VERSION 5.8 ;
BUSBITCHARS "[]" ;
DIVIDERCHAR "/" ;
UNITS
    DATABASE MICRONS 1000 ;
END UNITS

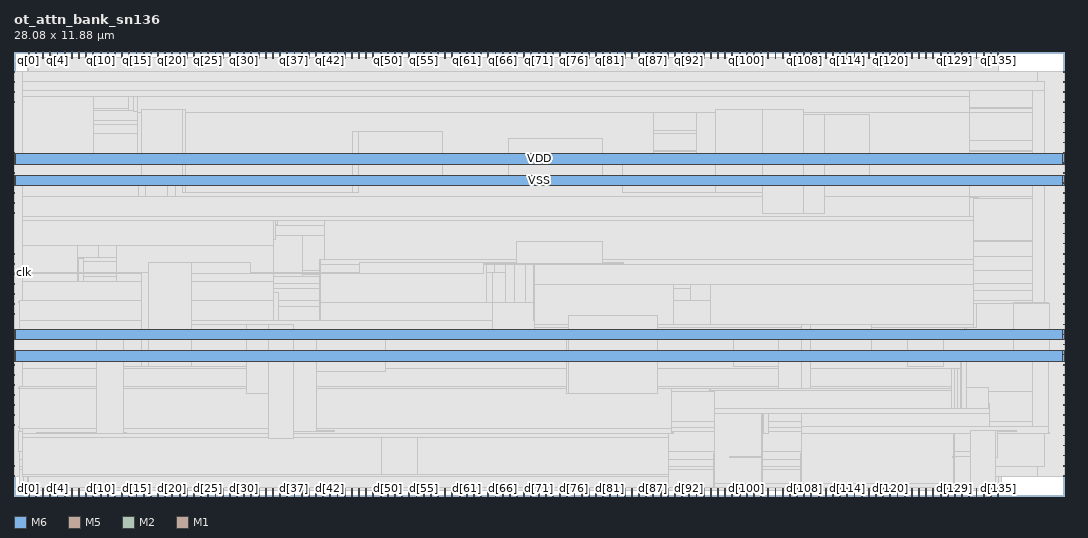
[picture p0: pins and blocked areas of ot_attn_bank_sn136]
MACRO ot_attn_bank_sn136
  FOREIGN ot_attn_bank_sn136 0 0 ;
  CLASS BLOCK ;
  SIZE 28.08 BY 11.88 ;
  PIN clk
    DIRECTION INPUT ;
    USE SIGNAL ;
    PORT
      LAYER M6 ;
        RECT  0 5.952 0.192 5.984 ;
    END
  END clk
  PIN d[0]
    DIRECTION INPUT ;
    USE SIGNAL ;
    PORT
      LAYER M5 ;
        RECT  0.384 0 0.408 0.192 ;
    END
  END d[0]
  PIN d[100]
    DIRECTION INPUT ;
    USE SIGNAL ;
    PORT
      LAYER M5 ;
        RECT  19.584 0 19.608 0.192 ;
    END
  END d[100]
  PIN d[101]
    DIRECTION INPUT ;
    USE SIGNAL ;
    PORT
      LAYER M5 ;
        RECT  19.776 0 19.8 0.192 ;
    END
  END d[101]
  PIN d[102]
    DIRECTION INPUT ;
    USE SIGNAL ;
    PORT
      LAYER M5 ;
        RECT  19.968 0 19.992 0.192 ;
    END
  END d[102]
  PIN d[103]
    DIRECTION INPUT ;
    USE SIGNAL ;
    PORT
      LAYER M5 ;
        RECT  20.16 0 20.184 0.192 ;
    END
  END d[103]
  PIN d[104]
    DIRECTION INPUT ;
    USE SIGNAL ;
    PORT
      LAYER M5 ;
        RECT  20.352 0 20.376 0.192 ;
    END
  END d[104]
  PIN d[105]
    DIRECTION INPUT ;
    USE SIGNAL ;
    PORT
      LAYER M5 ;
        RECT  20.544 0 20.568 0.192 ;
    END
  END d[105]
  PIN d[106]
    DIRECTION INPUT ;
    USE SIGNAL ;
    PORT
      LAYER M5 ;
        RECT  20.736 0 20.76 0.192 ;
    END
  END d[106]
  PIN d[107]
    DIRECTION INPUT ;
    USE SIGNAL ;
    PORT
      LAYER M5 ;
        RECT  20.928 0 20.952 0.192 ;
    END
  END d[107]
  PIN d[108]
    DIRECTION INPUT ;
    USE SIGNAL ;
    PORT
      LAYER M5 ;
        RECT  21.12 0 21.144 0.192 ;
    END
  END d[108]
  PIN d[109]
    DIRECTION INPUT ;
    USE SIGNAL ;
    PORT
      LAYER M5 ;
        RECT  21.312 0 21.336 0.192 ;
    END
  END d[109]
  PIN d[10]
    DIRECTION INPUT ;
    USE SIGNAL ;
    PORT
      LAYER M5 ;
        RECT  2.304 0 2.328 0.192 ;
    END
  END d[10]
  PIN d[110]
    DIRECTION INPUT ;
    USE SIGNAL ;
    PORT
      LAYER M5 ;
        RECT  21.504 0 21.528 0.192 ;
    END
  END d[110]
  PIN d[111]
    DIRECTION INPUT ;
    USE SIGNAL ;
    PORT
      LAYER M5 ;
        RECT  21.696 0 21.72 0.192 ;
    END
  END d[111]
  PIN d[112]
    DIRECTION INPUT ;
    USE SIGNAL ;
    PORT
      LAYER M5 ;
        RECT  21.888 0 21.912 0.192 ;
    END
  END d[112]
  PIN d[113]
    DIRECTION INPUT ;
    USE SIGNAL ;
    PORT
      LAYER M5 ;
        RECT  22.08 0 22.104 0.192 ;
    END
  END d[113]
  PIN d[114]
    DIRECTION INPUT ;
    USE SIGNAL ;
    PORT
      LAYER M5 ;
        RECT  22.272 0 22.296 0.192 ;
    END
  END d[114]
  PIN d[115]
    DIRECTION INPUT ;
    USE SIGNAL ;
    PORT
      LAYER M5 ;
        RECT  22.464 0 22.488 0.192 ;
    END
  END d[115]
  PIN d[116]
    DIRECTION INPUT ;
    USE SIGNAL ;
    PORT
      LAYER M5 ;
        RECT  22.656 0 22.68 0.192 ;
    END
  END d[116]
  PIN d[117]
    DIRECTION INPUT ;
    USE SIGNAL ;
    PORT
      LAYER M5 ;
        RECT  22.848 0 22.872 0.192 ;
    END
  END d[117]
  PIN d[118]
    DIRECTION INPUT ;
    USE SIGNAL ;
    PORT
      LAYER M5 ;
        RECT  23.04 0 23.064 0.192 ;
    END
  END d[118]
  PIN d[119]
    DIRECTION INPUT ;
    USE SIGNAL ;
    PORT
      LAYER M5 ;
        RECT  23.232 0 23.256 0.192 ;
    END
  END d[119]
  PIN d[11]
    DIRECTION INPUT ;
    USE SIGNAL ;
    PORT
      LAYER M5 ;
        RECT  2.496 0 2.52 0.192 ;
    END
  END d[11]
  PIN d[120]
    DIRECTION INPUT ;
    USE SIGNAL ;
    PORT
      LAYER M5 ;
        RECT  23.424 0 23.448 0.192 ;
    END
  END d[120]
  PIN d[121]
    DIRECTION INPUT ;
    USE SIGNAL ;
    PORT
      LAYER M5 ;
        RECT  23.616 0 23.64 0.192 ;
    END
  END d[121]
  PIN d[122]
    DIRECTION INPUT ;
    USE SIGNAL ;
    PORT
      LAYER M5 ;
        RECT  23.808 0 23.832 0.192 ;
    END
  END d[122]
  PIN d[123]
    DIRECTION INPUT ;
    USE SIGNAL ;
    PORT
      LAYER M5 ;
        RECT  24 0 24.024 0.192 ;
    END
  END d[123]
  PIN d[124]
    DIRECTION INPUT ;
    USE SIGNAL ;
    PORT
      LAYER M5 ;
        RECT  24.192 0 24.216 0.192 ;
    END
  END d[124]
  PIN d[125]
    DIRECTION INPUT ;
    USE SIGNAL ;
    PORT
      LAYER M5 ;
        RECT  24.384 0 24.408 0.192 ;
    END
  END d[125]
  PIN d[126]
    DIRECTION INPUT ;
    USE SIGNAL ;
    PORT
      LAYER M5 ;
        RECT  24.576 0 24.6 0.192 ;
    END
  END d[126]
  PIN d[127]
    DIRECTION INPUT ;
    USE SIGNAL ;
    PORT
      LAYER M5 ;
        RECT  24.768 0 24.792 0.192 ;
    END
  END d[127]
  PIN d[128]
    DIRECTION INPUT ;
    USE SIGNAL ;
    PORT
      LAYER M5 ;
        RECT  24.96 0 24.984 0.192 ;
    END
  END d[128]
  PIN d[129]
    DIRECTION INPUT ;
    USE SIGNAL ;
    PORT
      LAYER M5 ;
        RECT  25.152 0 25.176 0.192 ;
    END
  END d[129]
  PIN d[12]
    DIRECTION INPUT ;
    USE SIGNAL ;
    PORT
      LAYER M5 ;
        RECT  2.688 0 2.712 0.192 ;
    END
  END d[12]
  PIN d[130]
    DIRECTION INPUT ;
    USE SIGNAL ;
    PORT
      LAYER M5 ;
        RECT  25.344 0 25.368 0.192 ;
    END
  END d[130]
  PIN d[131]
    DIRECTION INPUT ;
    USE SIGNAL ;
    PORT
      LAYER M5 ;
        RECT  25.536 0 25.56 0.192 ;
    END
  END d[131]
  PIN d[132]
    DIRECTION INPUT ;
    USE SIGNAL ;
    PORT
      LAYER M5 ;
        RECT  25.728 0 25.752 0.192 ;
    END
  END d[132]
  PIN d[133]
    DIRECTION INPUT ;
    USE SIGNAL ;
    PORT
      LAYER M5 ;
        RECT  25.92 0 25.944 0.192 ;
    END
  END d[133]
  PIN d[134]
    DIRECTION INPUT ;
    USE SIGNAL ;
    PORT
      LAYER M5 ;
        RECT  26.112 0 26.136 0.192 ;
    END
  END d[134]
  PIN d[135]
    DIRECTION INPUT ;
    USE SIGNAL ;
    PORT
      LAYER M5 ;
        RECT  26.304 0 26.328 0.192 ;
    END
  END d[135]
  PIN d[13]
    DIRECTION INPUT ;
    USE SIGNAL ;
    PORT
      LAYER M5 ;
        RECT  2.88 0 2.904 0.192 ;
    END
  END d[13]
  PIN d[14]
    DIRECTION INPUT ;
    USE SIGNAL ;
    PORT
      LAYER M5 ;
        RECT  3.072 0 3.096 0.192 ;
    END
  END d[14]
  PIN d[15]
    DIRECTION INPUT ;
    USE SIGNAL ;
    PORT
      LAYER M5 ;
        RECT  3.264 0 3.288 0.192 ;
    END
  END d[15]
  PIN d[16]
    DIRECTION INPUT ;
    USE SIGNAL ;
    PORT
      LAYER M5 ;
        RECT  3.456 0 3.48 0.192 ;
    END
  END d[16]
  PIN d[17]
    DIRECTION INPUT ;
    USE SIGNAL ;
    PORT
      LAYER M5 ;
        RECT  3.648 0 3.672 0.192 ;
    END
  END d[17]
  PIN d[18]
    DIRECTION INPUT ;
    USE SIGNAL ;
    PORT
      LAYER M5 ;
        RECT  3.84 0 3.864 0.192 ;
    END
  END d[18]
  PIN d[19]
    DIRECTION INPUT ;
    USE SIGNAL ;
    PORT
      LAYER M5 ;
        RECT  4.032 0 4.056 0.192 ;
    END
  END d[19]
  PIN d[1]
    DIRECTION INPUT ;
    USE SIGNAL ;
    PORT
      LAYER M5 ;
        RECT  0.576 0 0.6 0.192 ;
    END
  END d[1]
  PIN d[20]
    DIRECTION INPUT ;
    USE SIGNAL ;
    PORT
      LAYER M5 ;
        RECT  4.224 0 4.248 0.192 ;
    END
  END d[20]
  PIN d[21]
    DIRECTION INPUT ;
    USE SIGNAL ;
    PORT
      LAYER M5 ;
        RECT  4.416 0 4.44 0.192 ;
    END
  END d[21]
  PIN d[22]
    DIRECTION INPUT ;
    USE SIGNAL ;
    PORT
      LAYER M5 ;
        RECT  4.608 0 4.632 0.192 ;
    END
  END d[22]
  PIN d[23]
    DIRECTION INPUT ;
    USE SIGNAL ;
    PORT
      LAYER M5 ;
        RECT  4.8 0 4.824 0.192 ;
    END
  END d[23]
  PIN d[24]
    DIRECTION INPUT ;
    USE SIGNAL ;
    PORT
      LAYER M5 ;
        RECT  4.992 0 5.016 0.192 ;
    END
  END d[24]
  PIN d[25]
    DIRECTION INPUT ;
    USE SIGNAL ;
    PORT
      LAYER M5 ;
        RECT  5.184 0 5.208 0.192 ;
    END
  END d[25]
  PIN d[26]
    DIRECTION INPUT ;
    USE SIGNAL ;
    PORT
      LAYER M5 ;
        RECT  5.376 0 5.4 0.192 ;
    END
  END d[26]
  PIN d[27]
    DIRECTION INPUT ;
    USE SIGNAL ;
    PORT
      LAYER M5 ;
        RECT  5.568 0 5.592 0.192 ;
    END
  END d[27]
  PIN d[28]
    DIRECTION INPUT ;
    USE SIGNAL ;
    PORT
      LAYER M5 ;
        RECT  5.76 0 5.784 0.192 ;
    END
  END d[28]
  PIN d[29]
    DIRECTION INPUT ;
    USE SIGNAL ;
    PORT
      LAYER M5 ;
        RECT  5.952 0 5.976 0.192 ;
    END
  END d[29]
  PIN d[2]
    DIRECTION INPUT ;
    USE SIGNAL ;
    PORT
      LAYER M5 ;
        RECT  0.768 0 0.792 0.192 ;
    END
  END d[2]
  PIN d[30]
    DIRECTION INPUT ;
    USE SIGNAL ;
    PORT
      LAYER M5 ;
        RECT  6.144 0 6.168 0.192 ;
    END
  END d[30]
  PIN d[31]
    DIRECTION INPUT ;
    USE SIGNAL ;
    PORT
      LAYER M5 ;
        RECT  6.336 0 6.36 0.192 ;
    END
  END d[31]
  PIN d[32]
    DIRECTION INPUT ;
    USE SIGNAL ;
    PORT
      LAYER M5 ;
        RECT  6.528 0 6.552 0.192 ;
    END
  END d[32]
  PIN d[33]
    DIRECTION INPUT ;
    USE SIGNAL ;
    PORT
      LAYER M5 ;
        RECT  6.72 0 6.744 0.192 ;
    END
  END d[33]
  PIN d[34]
    DIRECTION INPUT ;
    USE SIGNAL ;
    PORT
      LAYER M5 ;
        RECT  6.912 0 6.936 0.192 ;
    END
  END d[34]
  PIN d[35]
    DIRECTION INPUT ;
    USE SIGNAL ;
    PORT
      LAYER M5 ;
        RECT  7.104 0 7.128 0.192 ;
    END
  END d[35]
  PIN d[36]
    DIRECTION INPUT ;
    USE SIGNAL ;
    PORT
      LAYER M5 ;
        RECT  7.296 0 7.32 0.192 ;
    END
  END d[36]
  PIN d[37]
    DIRECTION INPUT ;
    USE SIGNAL ;
    PORT
      LAYER M5 ;
        RECT  7.488 0 7.512 0.192 ;
    END
  END d[37]
  PIN d[38]
    DIRECTION INPUT ;
    USE SIGNAL ;
    PORT
      LAYER M5 ;
        RECT  7.68 0 7.704 0.192 ;
    END
  END d[38]
  PIN d[39]
    DIRECTION INPUT ;
    USE SIGNAL ;
    PORT
      LAYER M5 ;
        RECT  7.872 0 7.896 0.192 ;
    END
  END d[39]
  PIN d[3]
    DIRECTION INPUT ;
    USE SIGNAL ;
    PORT
      LAYER M5 ;
        RECT  0.96 0 0.984 0.192 ;
    END
  END d[3]
  PIN d[40]
    DIRECTION INPUT ;
    USE SIGNAL ;
    PORT
      LAYER M5 ;
        RECT  8.064 0 8.088 0.192 ;
    END
  END d[40]
  PIN d[41]
    DIRECTION INPUT ;
    USE SIGNAL ;
    PORT
      LAYER M5 ;
        RECT  8.256 0 8.28 0.192 ;
    END
  END d[41]
  PIN d[42]
    DIRECTION INPUT ;
    USE SIGNAL ;
    PORT
      LAYER M5 ;
        RECT  8.448 0 8.472 0.192 ;
    END
  END d[42]
  PIN d[43]
    DIRECTION INPUT ;
    USE SIGNAL ;
    PORT
      LAYER M5 ;
        RECT  8.64 0 8.664 0.192 ;
    END
  END d[43]
  PIN d[44]
    DIRECTION INPUT ;
    USE SIGNAL ;
    PORT
      LAYER M5 ;
        RECT  8.832 0 8.856 0.192 ;
    END
  END d[44]
  PIN d[45]
    DIRECTION INPUT ;
    USE SIGNAL ;
    PORT
      LAYER M5 ;
        RECT  9.024 0 9.048 0.192 ;
    END
  END d[45]
  PIN d[46]
    DIRECTION INPUT ;
    USE SIGNAL ;
    PORT
      LAYER M5 ;
        RECT  9.216 0 9.24 0.192 ;
    END
  END d[46]
  PIN d[47]
    DIRECTION INPUT ;
    USE SIGNAL ;
    PORT
      LAYER M5 ;
        RECT  9.408 0 9.432 0.192 ;
    END
  END d[47]
  PIN d[48]
    DIRECTION INPUT ;
    USE SIGNAL ;
    PORT
      LAYER M5 ;
        RECT  9.6 0 9.624 0.192 ;
    END
  END d[48]
  PIN d[49]
    DIRECTION INPUT ;
    USE SIGNAL ;
    PORT
      LAYER M5 ;
        RECT  9.792 0 9.816 0.192 ;
    END
  END d[49]
  PIN d[4]
    DIRECTION INPUT ;
    USE SIGNAL ;
    PORT
      LAYER M5 ;
        RECT  1.152 0 1.176 0.192 ;
    END
  END d[4]
  PIN d[50]
    DIRECTION INPUT ;
    USE SIGNAL ;
    PORT
      LAYER M5 ;
        RECT  9.984 0 10.008 0.192 ;
    END
  END d[50]
  PIN d[51]
    DIRECTION INPUT ;
    USE SIGNAL ;
    PORT
      LAYER M5 ;
        RECT  10.176 0 10.2 0.192 ;
    END
  END d[51]
  PIN d[52]
    DIRECTION INPUT ;
    USE SIGNAL ;
    PORT
      LAYER M5 ;
        RECT  10.368 0 10.392 0.192 ;
    END
  END d[52]
  PIN d[53]
    DIRECTION INPUT ;
    USE SIGNAL ;
    PORT
      LAYER M5 ;
        RECT  10.56 0 10.584 0.192 ;
    END
  END d[53]
  PIN d[54]
    DIRECTION INPUT ;
    USE SIGNAL ;
    PORT
      LAYER M5 ;
        RECT  10.752 0 10.776 0.192 ;
    END
  END d[54]
  PIN d[55]
    DIRECTION INPUT ;
    USE SIGNAL ;
    PORT
      LAYER M5 ;
        RECT  10.944 0 10.968 0.192 ;
    END
  END d[55]
  PIN d[56]
    DIRECTION INPUT ;
    USE SIGNAL ;
    PORT
      LAYER M5 ;
        RECT  11.136 0 11.16 0.192 ;
    END
  END d[56]
  PIN d[57]
    DIRECTION INPUT ;
    USE SIGNAL ;
    PORT
      LAYER M5 ;
        RECT  11.328 0 11.352 0.192 ;
    END
  END d[57]
  PIN d[58]
    DIRECTION INPUT ;
    USE SIGNAL ;
    PORT
      LAYER M5 ;
        RECT  11.52 0 11.544 0.192 ;
    END
  END d[58]
  PIN d[59]
    DIRECTION INPUT ;
    USE SIGNAL ;
    PORT
      LAYER M5 ;
        RECT  11.712 0 11.736 0.192 ;
    END
  END d[59]
  PIN d[5]
    DIRECTION INPUT ;
    USE SIGNAL ;
    PORT
      LAYER M5 ;
        RECT  1.344 0 1.368 0.192 ;
    END
  END d[5]
  PIN d[60]
    DIRECTION INPUT ;
    USE SIGNAL ;
    PORT
      LAYER M5 ;
        RECT  11.904 0 11.928 0.192 ;
    END
  END d[60]
  PIN d[61]
    DIRECTION INPUT ;
    USE SIGNAL ;
    PORT
      LAYER M5 ;
        RECT  12.096 0 12.12 0.192 ;
    END
  END d[61]
  PIN d[62]
    DIRECTION INPUT ;
    USE SIGNAL ;
    PORT
      LAYER M5 ;
        RECT  12.288 0 12.312 0.192 ;
    END
  END d[62]
  PIN d[63]
    DIRECTION INPUT ;
    USE SIGNAL ;
    PORT
      LAYER M5 ;
        RECT  12.48 0 12.504 0.192 ;
    END
  END d[63]
  PIN d[64]
    DIRECTION INPUT ;
    USE SIGNAL ;
    PORT
      LAYER M5 ;
        RECT  12.672 0 12.696 0.192 ;
    END
  END d[64]
  PIN d[65]
    DIRECTION INPUT ;
    USE SIGNAL ;
    PORT
      LAYER M5 ;
        RECT  12.864 0 12.888 0.192 ;
    END
  END d[65]
  PIN d[66]
    DIRECTION INPUT ;
    USE SIGNAL ;
    PORT
      LAYER M5 ;
        RECT  13.056 0 13.08 0.192 ;
    END
  END d[66]
  PIN d[67]
    DIRECTION INPUT ;
    USE SIGNAL ;
    PORT
      LAYER M5 ;
        RECT  13.248 0 13.272 0.192 ;
    END
  END d[67]
  PIN d[68]
    DIRECTION INPUT ;
    USE SIGNAL ;
    PORT
      LAYER M5 ;
        RECT  13.44 0 13.464 0.192 ;
    END
  END d[68]
  PIN d[69]
    DIRECTION INPUT ;
    USE SIGNAL ;
    PORT
      LAYER M5 ;
        RECT  13.632 0 13.656 0.192 ;
    END
  END d[69]
  PIN d[6]
    DIRECTION INPUT ;
    USE SIGNAL ;
    PORT
      LAYER M5 ;
        RECT  1.536 0 1.56 0.192 ;
    END
  END d[6]
  PIN d[70]
    DIRECTION INPUT ;
    USE SIGNAL ;
    PORT
      LAYER M5 ;
        RECT  13.824 0 13.848 0.192 ;
    END
  END d[70]
  PIN d[71]
    DIRECTION INPUT ;
    USE SIGNAL ;
    PORT
      LAYER M5 ;
        RECT  14.016 0 14.04 0.192 ;
    END
  END d[71]
  PIN d[72]
    DIRECTION INPUT ;
    USE SIGNAL ;
    PORT
      LAYER M5 ;
        RECT  14.208 0 14.232 0.192 ;
    END
  END d[72]
  PIN d[73]
    DIRECTION INPUT ;
    USE SIGNAL ;
    PORT
      LAYER M5 ;
        RECT  14.4 0 14.424 0.192 ;
    END
  END d[73]
  PIN d[74]
    DIRECTION INPUT ;
    USE SIGNAL ;
    PORT
      LAYER M5 ;
        RECT  14.592 0 14.616 0.192 ;
    END
  END d[74]
  PIN d[75]
    DIRECTION INPUT ;
    USE SIGNAL ;
    PORT
      LAYER M5 ;
        RECT  14.784 0 14.808 0.192 ;
    END
  END d[75]
  PIN d[76]
    DIRECTION INPUT ;
    USE SIGNAL ;
    PORT
      LAYER M5 ;
        RECT  14.976 0 15 0.192 ;
    END
  END d[76]
  PIN d[77]
    DIRECTION INPUT ;
    USE SIGNAL ;
    PORT
      LAYER M5 ;
        RECT  15.168 0 15.192 0.192 ;
    END
  END d[77]
  PIN d[78]
    DIRECTION INPUT ;
    USE SIGNAL ;
    PORT
      LAYER M5 ;
        RECT  15.36 0 15.384 0.192 ;
    END
  END d[78]
  PIN d[79]
    DIRECTION INPUT ;
    USE SIGNAL ;
    PORT
      LAYER M5 ;
        RECT  15.552 0 15.576 0.192 ;
    END
  END d[79]
  PIN d[7]
    DIRECTION INPUT ;
    USE SIGNAL ;
    PORT
      LAYER M5 ;
        RECT  1.728 0 1.752 0.192 ;
    END
  END d[7]
  PIN d[80]
    DIRECTION INPUT ;
    USE SIGNAL ;
    PORT
      LAYER M5 ;
        RECT  15.744 0 15.768 0.192 ;
    END
  END d[80]
  PIN d[81]
    DIRECTION INPUT ;
    USE SIGNAL ;
    PORT
      LAYER M5 ;
        RECT  15.936 0 15.96 0.192 ;
    END
  END d[81]
  PIN d[82]
    DIRECTION INPUT ;
    USE SIGNAL ;
    PORT
      LAYER M5 ;
        RECT  16.128 0 16.152 0.192 ;
    END
  END d[82]
  PIN d[83]
    DIRECTION INPUT ;
    USE SIGNAL ;
    PORT
      LAYER M5 ;
        RECT  16.32 0 16.344 0.192 ;
    END
  END d[83]
  PIN d[84]
    DIRECTION INPUT ;
    USE SIGNAL ;
    PORT
      LAYER M5 ;
        RECT  16.512 0 16.536 0.192 ;
    END
  END d[84]
  PIN d[85]
    DIRECTION INPUT ;
    USE SIGNAL ;
    PORT
      LAYER M5 ;
        RECT  16.704 0 16.728 0.192 ;
    END
  END d[85]
  PIN d[86]
    DIRECTION INPUT ;
    USE SIGNAL ;
    PORT
      LAYER M5 ;
        RECT  16.896 0 16.92 0.192 ;
    END
  END d[86]
  PIN d[87]
    DIRECTION INPUT ;
    USE SIGNAL ;
    PORT
      LAYER M5 ;
        RECT  17.088 0 17.112 0.192 ;
    END
  END d[87]
  PIN d[88]
    DIRECTION INPUT ;
    USE SIGNAL ;
    PORT
      LAYER M5 ;
        RECT  17.28 0 17.304 0.192 ;
    END
  END d[88]
  PIN d[89]
    DIRECTION INPUT ;
    USE SIGNAL ;
    PORT
      LAYER M5 ;
        RECT  17.472 0 17.496 0.192 ;
    END
  END d[89]
  PIN d[8]
    DIRECTION INPUT ;
    USE SIGNAL ;
    PORT
      LAYER M5 ;
        RECT  1.92 0 1.944 0.192 ;
    END
  END d[8]
  PIN d[90]
    DIRECTION INPUT ;
    USE SIGNAL ;
    PORT
      LAYER M5 ;
        RECT  17.664 0 17.688 0.192 ;
    END
  END d[90]
  PIN d[91]
    DIRECTION INPUT ;
    USE SIGNAL ;
    PORT
      LAYER M5 ;
        RECT  17.856 0 17.88 0.192 ;
    END
  END d[91]
  PIN d[92]
    DIRECTION INPUT ;
    USE SIGNAL ;
    PORT
      LAYER M5 ;
        RECT  18.048 0 18.072 0.192 ;
    END
  END d[92]
  PIN d[93]
    DIRECTION INPUT ;
    USE SIGNAL ;
    PORT
      LAYER M5 ;
        RECT  18.24 0 18.264 0.192 ;
    END
  END d[93]
  PIN d[94]
    DIRECTION INPUT ;
    USE SIGNAL ;
    PORT
      LAYER M5 ;
        RECT  18.432 0 18.456 0.192 ;
    END
  END d[94]
  PIN d[95]
    DIRECTION INPUT ;
    USE SIGNAL ;
    PORT
      LAYER M5 ;
        RECT  18.624 0 18.648 0.192 ;
    END
  END d[95]
  PIN d[96]
    DIRECTION INPUT ;
    USE SIGNAL ;
    PORT
      LAYER M5 ;
        RECT  18.816 0 18.84 0.192 ;
    END
  END d[96]
  PIN d[97]
    DIRECTION INPUT ;
    USE SIGNAL ;
    PORT
      LAYER M5 ;
        RECT  19.008 0 19.032 0.192 ;
    END
  END d[97]
  PIN d[98]
    DIRECTION INPUT ;
    USE SIGNAL ;
    PORT
      LAYER M5 ;
        RECT  19.2 0 19.224 0.192 ;
    END
  END d[98]
  PIN d[99]
    DIRECTION INPUT ;
    USE SIGNAL ;
    PORT
      LAYER M5 ;
        RECT  19.392 0 19.416 0.192 ;
    END
  END d[99]
  PIN d[9]
    DIRECTION INPUT ;
    USE SIGNAL ;
    PORT
      LAYER M5 ;
        RECT  2.112 0 2.136 0.192 ;
    END
  END d[9]
  PIN q[0]
    DIRECTION OUTPUT ;
    USE SIGNAL ;
    PORT
      LAYER M5 ;
        RECT  0.384 11.688 0.408 11.88 ;
    END
  END q[0]
  PIN q[100]
    DIRECTION OUTPUT ;
    USE SIGNAL ;
    PORT
      LAYER M5 ;
        RECT  19.584 11.688 19.608 11.88 ;
    END
  END q[100]
  PIN q[101]
    DIRECTION OUTPUT ;
    USE SIGNAL ;
    PORT
      LAYER M5 ;
        RECT  19.776 11.688 19.8 11.88 ;
    END
  END q[101]
  PIN q[102]
    DIRECTION OUTPUT ;
    USE SIGNAL ;
    PORT
      LAYER M5 ;
        RECT  19.968 11.688 19.992 11.88 ;
    END
  END q[102]
  PIN q[103]
    DIRECTION OUTPUT ;
    USE SIGNAL ;
    PORT
      LAYER M5 ;
        RECT  20.16 11.688 20.184 11.88 ;
    END
  END q[103]
  PIN q[104]
    DIRECTION OUTPUT ;
    USE SIGNAL ;
    PORT
      LAYER M5 ;
        RECT  20.352 11.688 20.376 11.88 ;
    END
  END q[104]
  PIN q[105]
    DIRECTION OUTPUT ;
    USE SIGNAL ;
    PORT
      LAYER M5 ;
        RECT  20.544 11.688 20.568 11.88 ;
    END
  END q[105]
  PIN q[106]
    DIRECTION OUTPUT ;
    USE SIGNAL ;
    PORT
      LAYER M5 ;
        RECT  20.736 11.688 20.76 11.88 ;
    END
  END q[106]
  PIN q[107]
    DIRECTION OUTPUT ;
    USE SIGNAL ;
    PORT
      LAYER M5 ;
        RECT  20.928 11.688 20.952 11.88 ;
    END
  END q[107]
  PIN q[108]
    DIRECTION OUTPUT ;
    USE SIGNAL ;
    PORT
      LAYER M5 ;
        RECT  21.12 11.688 21.144 11.88 ;
    END
  END q[108]
  PIN q[109]
    DIRECTION OUTPUT ;
    USE SIGNAL ;
    PORT
      LAYER M5 ;
        RECT  21.312 11.688 21.336 11.88 ;
    END
  END q[109]
  PIN q[10]
    DIRECTION OUTPUT ;
    USE SIGNAL ;
    PORT
      LAYER M5 ;
        RECT  2.304 11.688 2.328 11.88 ;
    END
  END q[10]
  PIN q[110]
    DIRECTION OUTPUT ;
    USE SIGNAL ;
    PORT
      LAYER M5 ;
        RECT  21.504 11.688 21.528 11.88 ;
    END
  END q[110]
  PIN q[111]
    DIRECTION OUTPUT ;
    USE SIGNAL ;
    PORT
      LAYER M5 ;
        RECT  21.696 11.688 21.72 11.88 ;
    END
  END q[111]
  PIN q[112]
    DIRECTION OUTPUT ;
    USE SIGNAL ;
    PORT
      LAYER M5 ;
        RECT  21.888 11.688 21.912 11.88 ;
    END
  END q[112]
  PIN q[113]
    DIRECTION OUTPUT ;
    USE SIGNAL ;
    PORT
      LAYER M5 ;
        RECT  22.08 11.688 22.104 11.88 ;
    END
  END q[113]
  PIN q[114]
    DIRECTION OUTPUT ;
    USE SIGNAL ;
    PORT
      LAYER M5 ;
        RECT  22.272 11.688 22.296 11.88 ;
    END
  END q[114]
  PIN q[115]
    DIRECTION OUTPUT ;
    USE SIGNAL ;
    PORT
      LAYER M5 ;
        RECT  22.464 11.688 22.488 11.88 ;
    END
  END q[115]
  PIN q[116]
    DIRECTION OUTPUT ;
    USE SIGNAL ;
    PORT
      LAYER M5 ;
        RECT  22.656 11.688 22.68 11.88 ;
    END
  END q[116]
  PIN q[117]
    DIRECTION OUTPUT ;
    USE SIGNAL ;
    PORT
      LAYER M5 ;
        RECT  22.848 11.688 22.872 11.88 ;
    END
  END q[117]
  PIN q[118]
    DIRECTION OUTPUT ;
    USE SIGNAL ;
    PORT
      LAYER M5 ;
        RECT  23.04 11.688 23.064 11.88 ;
    END
  END q[118]
  PIN q[119]
    DIRECTION OUTPUT ;
    USE SIGNAL ;
    PORT
      LAYER M5 ;
        RECT  23.232 11.688 23.256 11.88 ;
    END
  END q[119]
  PIN q[11]
    DIRECTION OUTPUT ;
    USE SIGNAL ;
    PORT
      LAYER M5 ;
        RECT  2.496 11.688 2.52 11.88 ;
    END
  END q[11]
  PIN q[120]
    DIRECTION OUTPUT ;
    USE SIGNAL ;
    PORT
      LAYER M5 ;
        RECT  23.424 11.688 23.448 11.88 ;
    END
  END q[120]
  PIN q[121]
    DIRECTION OUTPUT ;
    USE SIGNAL ;
    PORT
      LAYER M5 ;
        RECT  23.616 11.688 23.64 11.88 ;
    END
  END q[121]
  PIN q[122]
    DIRECTION OUTPUT ;
    USE SIGNAL ;
    PORT
      LAYER M5 ;
        RECT  23.808 11.688 23.832 11.88 ;
    END
  END q[122]
  PIN q[123]
    DIRECTION OUTPUT ;
    USE SIGNAL ;
    PORT
      LAYER M5 ;
        RECT  24 11.688 24.024 11.88 ;
    END
  END q[123]
  PIN q[124]
    DIRECTION OUTPUT ;
    USE SIGNAL ;
    PORT
      LAYER M5 ;
        RECT  24.192 11.688 24.216 11.88 ;
    END
  END q[124]
  PIN q[125]
    DIRECTION OUTPUT ;
    USE SIGNAL ;
    PORT
      LAYER M5 ;
        RECT  24.384 11.688 24.408 11.88 ;
    END
  END q[125]
  PIN q[126]
    DIRECTION OUTPUT ;
    USE SIGNAL ;
    PORT
      LAYER M5 ;
        RECT  24.576 11.688 24.6 11.88 ;
    END
  END q[126]
  PIN q[127]
    DIRECTION OUTPUT ;
    USE SIGNAL ;
    PORT
      LAYER M5 ;
        RECT  24.768 11.688 24.792 11.88 ;
    END
  END q[127]
  PIN q[128]
    DIRECTION OUTPUT ;
    USE SIGNAL ;
    PORT
      LAYER M5 ;
        RECT  24.96 11.688 24.984 11.88 ;
    END
  END q[128]
  PIN q[129]
    DIRECTION OUTPUT ;
    USE SIGNAL ;
    PORT
      LAYER M5 ;
        RECT  25.152 11.688 25.176 11.88 ;
    END
  END q[129]
  PIN q[12]
    DIRECTION OUTPUT ;
    USE SIGNAL ;
    PORT
      LAYER M5 ;
        RECT  2.688 11.688 2.712 11.88 ;
    END
  END q[12]
  PIN q[130]
    DIRECTION OUTPUT ;
    USE SIGNAL ;
    PORT
      LAYER M5 ;
        RECT  25.344 11.688 25.368 11.88 ;
    END
  END q[130]
  PIN q[131]
    DIRECTION OUTPUT ;
    USE SIGNAL ;
    PORT
      LAYER M5 ;
        RECT  25.536 11.688 25.56 11.88 ;
    END
  END q[131]
  PIN q[132]
    DIRECTION OUTPUT ;
    USE SIGNAL ;
    PORT
      LAYER M5 ;
        RECT  25.728 11.688 25.752 11.88 ;
    END
  END q[132]
  PIN q[133]
    DIRECTION OUTPUT ;
    USE SIGNAL ;
    PORT
      LAYER M5 ;
        RECT  25.92 11.688 25.944 11.88 ;
    END
  END q[133]
  PIN q[134]
    DIRECTION OUTPUT ;
    USE SIGNAL ;
    PORT
      LAYER M5 ;
        RECT  26.112 11.688 26.136 11.88 ;
    END
  END q[134]
  PIN q[135]
    DIRECTION OUTPUT ;
    USE SIGNAL ;
    PORT
      LAYER M5 ;
        RECT  26.304 11.688 26.328 11.88 ;
    END
  END q[135]
  PIN q[13]
    DIRECTION OUTPUT ;
    USE SIGNAL ;
    PORT
      LAYER M5 ;
        RECT  2.88 11.688 2.904 11.88 ;
    END
  END q[13]
  PIN q[14]
    DIRECTION OUTPUT ;
    USE SIGNAL ;
    PORT
      LAYER M5 ;
        RECT  3.072 11.688 3.096 11.88 ;
    END
  END q[14]
  PIN q[15]
    DIRECTION OUTPUT ;
    USE SIGNAL ;
    PORT
      LAYER M5 ;
        RECT  3.264 11.688 3.288 11.88 ;
    END
  END q[15]
  PIN q[16]
    DIRECTION OUTPUT ;
    USE SIGNAL ;
    PORT
      LAYER M5 ;
        RECT  3.456 11.688 3.48 11.88 ;
    END
  END q[16]
  PIN q[17]
    DIRECTION OUTPUT ;
    USE SIGNAL ;
    PORT
      LAYER M5 ;
        RECT  3.648 11.688 3.672 11.88 ;
    END
  END q[17]
  PIN q[18]
    DIRECTION OUTPUT ;
    USE SIGNAL ;
    PORT
      LAYER M5 ;
        RECT  3.84 11.688 3.864 11.88 ;
    END
  END q[18]
  PIN q[19]
    DIRECTION OUTPUT ;
    USE SIGNAL ;
    PORT
      LAYER M5 ;
        RECT  4.032 11.688 4.056 11.88 ;
    END
  END q[19]
  PIN q[1]
    DIRECTION OUTPUT ;
    USE SIGNAL ;
    PORT
      LAYER M5 ;
        RECT  0.576 11.688 0.6 11.88 ;
    END
  END q[1]
  PIN q[20]
    DIRECTION OUTPUT ;
    USE SIGNAL ;
    PORT
      LAYER M5 ;
        RECT  4.224 11.688 4.248 11.88 ;
    END
  END q[20]
  PIN q[21]
    DIRECTION OUTPUT ;
    USE SIGNAL ;
    PORT
      LAYER M5 ;
        RECT  4.416 11.688 4.44 11.88 ;
    END
  END q[21]
  PIN q[22]
    DIRECTION OUTPUT ;
    USE SIGNAL ;
    PORT
      LAYER M5 ;
        RECT  4.608 11.688 4.632 11.88 ;
    END
  END q[22]
  PIN q[23]
    DIRECTION OUTPUT ;
    USE SIGNAL ;
    PORT
      LAYER M5 ;
        RECT  4.8 11.688 4.824 11.88 ;
    END
  END q[23]
  PIN q[24]
    DIRECTION OUTPUT ;
    USE SIGNAL ;
    PORT
      LAYER M5 ;
        RECT  4.992 11.688 5.016 11.88 ;
    END
  END q[24]
  PIN q[25]
    DIRECTION OUTPUT ;
    USE SIGNAL ;
    PORT
      LAYER M5 ;
        RECT  5.184 11.688 5.208 11.88 ;
    END
  END q[25]
  PIN q[26]
    DIRECTION OUTPUT ;
    USE SIGNAL ;
    PORT
      LAYER M5 ;
        RECT  5.376 11.688 5.4 11.88 ;
    END
  END q[26]
  PIN q[27]
    DIRECTION OUTPUT ;
    USE SIGNAL ;
    PORT
      LAYER M5 ;
        RECT  5.568 11.688 5.592 11.88 ;
    END
  END q[27]
  PIN q[28]
    DIRECTION OUTPUT ;
    USE SIGNAL ;
    PORT
      LAYER M5 ;
        RECT  5.76 11.688 5.784 11.88 ;
    END
  END q[28]
  PIN q[29]
    DIRECTION OUTPUT ;
    USE SIGNAL ;
    PORT
      LAYER M5 ;
        RECT  5.952 11.688 5.976 11.88 ;
    END
  END q[29]
  PIN q[2]
    DIRECTION OUTPUT ;
    USE SIGNAL ;
    PORT
      LAYER M5 ;
        RECT  0.768 11.688 0.792 11.88 ;
    END
  END q[2]
  PIN q[30]
    DIRECTION OUTPUT ;
    USE SIGNAL ;
    PORT
      LAYER M5 ;
        RECT  6.144 11.688 6.168 11.88 ;
    END
  END q[30]
  PIN q[31]
    DIRECTION OUTPUT ;
    USE SIGNAL ;
    PORT
      LAYER M5 ;
        RECT  6.336 11.688 6.36 11.88 ;
    END
  END q[31]
  PIN q[32]
    DIRECTION OUTPUT ;
    USE SIGNAL ;
    PORT
      LAYER M5 ;
        RECT  6.528 11.688 6.552 11.88 ;
    END
  END q[32]
  PIN q[33]
    DIRECTION OUTPUT ;
    USE SIGNAL ;
    PORT
      LAYER M5 ;
        RECT  6.72 11.688 6.744 11.88 ;
    END
  END q[33]
  PIN q[34]
    DIRECTION OUTPUT ;
    USE SIGNAL ;
    PORT
      LAYER M5 ;
        RECT  6.912 11.688 6.936 11.88 ;
    END
  END q[34]
  PIN q[35]
    DIRECTION OUTPUT ;
    USE SIGNAL ;
    PORT
      LAYER M5 ;
        RECT  7.104 11.688 7.128 11.88 ;
    END
  END q[35]
  PIN q[36]
    DIRECTION OUTPUT ;
    USE SIGNAL ;
    PORT
      LAYER M5 ;
        RECT  7.296 11.688 7.32 11.88 ;
    END
  END q[36]
  PIN q[37]
    DIRECTION OUTPUT ;
    USE SIGNAL ;
    PORT
      LAYER M5 ;
        RECT  7.488 11.688 7.512 11.88 ;
    END
  END q[37]
  PIN q[38]
    DIRECTION OUTPUT ;
    USE SIGNAL ;
    PORT
      LAYER M5 ;
        RECT  7.68 11.688 7.704 11.88 ;
    END
  END q[38]
  PIN q[39]
    DIRECTION OUTPUT ;
    USE SIGNAL ;
    PORT
      LAYER M5 ;
        RECT  7.872 11.688 7.896 11.88 ;
    END
  END q[39]
  PIN q[3]
    DIRECTION OUTPUT ;
    USE SIGNAL ;
    PORT
      LAYER M5 ;
        RECT  0.96 11.688 0.984 11.88 ;
    END
  END q[3]
  PIN q[40]
    DIRECTION OUTPUT ;
    USE SIGNAL ;
    PORT
      LAYER M5 ;
        RECT  8.064 11.688 8.088 11.88 ;
    END
  END q[40]
  PIN q[41]
    DIRECTION OUTPUT ;
    USE SIGNAL ;
    PORT
      LAYER M5 ;
        RECT  8.256 11.688 8.28 11.88 ;
    END
  END q[41]
  PIN q[42]
    DIRECTION OUTPUT ;
    USE SIGNAL ;
    PORT
      LAYER M5 ;
        RECT  8.448 11.688 8.472 11.88 ;
    END
  END q[42]
  PIN q[43]
    DIRECTION OUTPUT ;
    USE SIGNAL ;
    PORT
      LAYER M5 ;
        RECT  8.64 11.688 8.664 11.88 ;
    END
  END q[43]
  PIN q[44]
    DIRECTION OUTPUT ;
    USE SIGNAL ;
    PORT
      LAYER M5 ;
        RECT  8.832 11.688 8.856 11.88 ;
    END
  END q[44]
  PIN q[45]
    DIRECTION OUTPUT ;
    USE SIGNAL ;
    PORT
      LAYER M5 ;
        RECT  9.024 11.688 9.048 11.88 ;
    END
  END q[45]
  PIN q[46]
    DIRECTION OUTPUT ;
    USE SIGNAL ;
    PORT
      LAYER M5 ;
        RECT  9.216 11.688 9.24 11.88 ;
    END
  END q[46]
  PIN q[47]
    DIRECTION OUTPUT ;
    USE SIGNAL ;
    PORT
      LAYER M5 ;
        RECT  9.408 11.688 9.432 11.88 ;
    END
  END q[47]
  PIN q[48]
    DIRECTION OUTPUT ;
    USE SIGNAL ;
    PORT
      LAYER M5 ;
        RECT  9.6 11.688 9.624 11.88 ;
    END
  END q[48]
  PIN q[49]
    DIRECTION OUTPUT ;
    USE SIGNAL ;
    PORT
      LAYER M5 ;
        RECT  9.792 11.688 9.816 11.88 ;
    END
  END q[49]
  PIN q[4]
    DIRECTION OUTPUT ;
    USE SIGNAL ;
    PORT
      LAYER M5 ;
        RECT  1.152 11.688 1.176 11.88 ;
    END
  END q[4]
  PIN q[50]
    DIRECTION OUTPUT ;
    USE SIGNAL ;
    PORT
      LAYER M5 ;
        RECT  9.984 11.688 10.008 11.88 ;
    END
  END q[50]
  PIN q[51]
    DIRECTION OUTPUT ;
    USE SIGNAL ;
    PORT
      LAYER M5 ;
        RECT  10.176 11.688 10.2 11.88 ;
    END
  END q[51]
  PIN q[52]
    DIRECTION OUTPUT ;
    USE SIGNAL ;
    PORT
      LAYER M5 ;
        RECT  10.368 11.688 10.392 11.88 ;
    END
  END q[52]
  PIN q[53]
    DIRECTION OUTPUT ;
    USE SIGNAL ;
    PORT
      LAYER M5 ;
        RECT  10.56 11.688 10.584 11.88 ;
    END
  END q[53]
  PIN q[54]
    DIRECTION OUTPUT ;
    USE SIGNAL ;
    PORT
      LAYER M5 ;
        RECT  10.752 11.688 10.776 11.88 ;
    END
  END q[54]
  PIN q[55]
    DIRECTION OUTPUT ;
    USE SIGNAL ;
    PORT
      LAYER M5 ;
        RECT  10.944 11.688 10.968 11.88 ;
    END
  END q[55]
  PIN q[56]
    DIRECTION OUTPUT ;
    USE SIGNAL ;
    PORT
      LAYER M5 ;
        RECT  11.136 11.688 11.16 11.88 ;
    END
  END q[56]
  PIN q[57]
    DIRECTION OUTPUT ;
    USE SIGNAL ;
    PORT
      LAYER M5 ;
        RECT  11.328 11.688 11.352 11.88 ;
    END
  END q[57]
  PIN q[58]
    DIRECTION OUTPUT ;
    USE SIGNAL ;
    PORT
      LAYER M5 ;
        RECT  11.52 11.688 11.544 11.88 ;
    END
  END q[58]
  PIN q[59]
    DIRECTION OUTPUT ;
    USE SIGNAL ;
    PORT
      LAYER M5 ;
        RECT  11.712 11.688 11.736 11.88 ;
    END
  END q[59]
  PIN q[5]
    DIRECTION OUTPUT ;
    USE SIGNAL ;
    PORT
      LAYER M5 ;
        RECT  1.344 11.688 1.368 11.88 ;
    END
  END q[5]
  PIN q[60]
    DIRECTION OUTPUT ;
    USE SIGNAL ;
    PORT
      LAYER M5 ;
        RECT  11.904 11.688 11.928 11.88 ;
    END
  END q[60]
  PIN q[61]
    DIRECTION OUTPUT ;
    USE SIGNAL ;
    PORT
      LAYER M5 ;
        RECT  12.096 11.688 12.12 11.88 ;
    END
  END q[61]
  PIN q[62]
    DIRECTION OUTPUT ;
    USE SIGNAL ;
    PORT
      LAYER M5 ;
        RECT  12.288 11.688 12.312 11.88 ;
    END
  END q[62]
  PIN q[63]
    DIRECTION OUTPUT ;
    USE SIGNAL ;
    PORT
      LAYER M5 ;
        RECT  12.48 11.688 12.504 11.88 ;
    END
  END q[63]
  PIN q[64]
    DIRECTION OUTPUT ;
    USE SIGNAL ;
    PORT
      LAYER M5 ;
        RECT  12.672 11.688 12.696 11.88 ;
    END
  END q[64]
  PIN q[65]
    DIRECTION OUTPUT ;
    USE SIGNAL ;
    PORT
      LAYER M5 ;
        RECT  12.864 11.688 12.888 11.88 ;
    END
  END q[65]
  PIN q[66]
    DIRECTION OUTPUT ;
    USE SIGNAL ;
    PORT
      LAYER M5 ;
        RECT  13.056 11.688 13.08 11.88 ;
    END
  END q[66]
  PIN q[67]
    DIRECTION OUTPUT ;
    USE SIGNAL ;
    PORT
      LAYER M5 ;
        RECT  13.248 11.688 13.272 11.88 ;
    END
  END q[67]
  PIN q[68]
    DIRECTION OUTPUT ;
    USE SIGNAL ;
    PORT
      LAYER M5 ;
        RECT  13.44 11.688 13.464 11.88 ;
    END
  END q[68]
  PIN q[69]
    DIRECTION OUTPUT ;
    USE SIGNAL ;
    PORT
      LAYER M5 ;
        RECT  13.632 11.688 13.656 11.88 ;
    END
  END q[69]
  PIN q[6]
    DIRECTION OUTPUT ;
    USE SIGNAL ;
    PORT
      LAYER M5 ;
        RECT  1.536 11.688 1.56 11.88 ;
    END
  END q[6]
  PIN q[70]
    DIRECTION OUTPUT ;
    USE SIGNAL ;
    PORT
      LAYER M5 ;
        RECT  13.824 11.688 13.848 11.88 ;
    END
  END q[70]
  PIN q[71]
    DIRECTION OUTPUT ;
    USE SIGNAL ;
    PORT
      LAYER M5 ;
        RECT  14.016 11.688 14.04 11.88 ;
    END
  END q[71]
  PIN q[72]
    DIRECTION OUTPUT ;
    USE SIGNAL ;
    PORT
      LAYER M5 ;
        RECT  14.208 11.688 14.232 11.88 ;
    END
  END q[72]
  PIN q[73]
    DIRECTION OUTPUT ;
    USE SIGNAL ;
    PORT
      LAYER M5 ;
        RECT  14.4 11.688 14.424 11.88 ;
    END
  END q[73]
  PIN q[74]
    DIRECTION OUTPUT ;
    USE SIGNAL ;
    PORT
      LAYER M5 ;
        RECT  14.592 11.688 14.616 11.88 ;
    END
  END q[74]
  PIN q[75]
    DIRECTION OUTPUT ;
    USE SIGNAL ;
    PORT
      LAYER M5 ;
        RECT  14.784 11.688 14.808 11.88 ;
    END
  END q[75]
  PIN q[76]
    DIRECTION OUTPUT ;
    USE SIGNAL ;
    PORT
      LAYER M5 ;
        RECT  14.976 11.688 15 11.88 ;
    END
  END q[76]
  PIN q[77]
    DIRECTION OUTPUT ;
    USE SIGNAL ;
    PORT
      LAYER M5 ;
        RECT  15.168 11.688 15.192 11.88 ;
    END
  END q[77]
  PIN q[78]
    DIRECTION OUTPUT ;
    USE SIGNAL ;
    PORT
      LAYER M5 ;
        RECT  15.36 11.688 15.384 11.88 ;
    END
  END q[78]
  PIN q[79]
    DIRECTION OUTPUT ;
    USE SIGNAL ;
    PORT
      LAYER M5 ;
        RECT  15.552 11.688 15.576 11.88 ;
    END
  END q[79]
  PIN q[7]
    DIRECTION OUTPUT ;
    USE SIGNAL ;
    PORT
      LAYER M5 ;
        RECT  1.728 11.688 1.752 11.88 ;
    END
  END q[7]
  PIN q[80]
    DIRECTION OUTPUT ;
    USE SIGNAL ;
    PORT
      LAYER M5 ;
        RECT  15.744 11.688 15.768 11.88 ;
    END
  END q[80]
  PIN q[81]
    DIRECTION OUTPUT ;
    USE SIGNAL ;
    PORT
      LAYER M5 ;
        RECT  15.936 11.688 15.96 11.88 ;
    END
  END q[81]
  PIN q[82]
    DIRECTION OUTPUT ;
    USE SIGNAL ;
    PORT
      LAYER M5 ;
        RECT  16.128 11.688 16.152 11.88 ;
    END
  END q[82]
  PIN q[83]
    DIRECTION OUTPUT ;
    USE SIGNAL ;
    PORT
      LAYER M5 ;
        RECT  16.32 11.688 16.344 11.88 ;
    END
  END q[83]
  PIN q[84]
    DIRECTION OUTPUT ;
    USE SIGNAL ;
    PORT
      LAYER M5 ;
        RECT  16.512 11.688 16.536 11.88 ;
    END
  END q[84]
  PIN q[85]
    DIRECTION OUTPUT ;
    USE SIGNAL ;
    PORT
      LAYER M5 ;
        RECT  16.704 11.688 16.728 11.88 ;
    END
  END q[85]
  PIN q[86]
    DIRECTION OUTPUT ;
    USE SIGNAL ;
    PORT
      LAYER M5 ;
        RECT  16.896 11.688 16.92 11.88 ;
    END
  END q[86]
  PIN q[87]
    DIRECTION OUTPUT ;
    USE SIGNAL ;
    PORT
      LAYER M5 ;
        RECT  17.088 11.688 17.112 11.88 ;
    END
  END q[87]
  PIN q[88]
    DIRECTION OUTPUT ;
    USE SIGNAL ;
    PORT
      LAYER M5 ;
        RECT  17.28 11.688 17.304 11.88 ;
    END
  END q[88]
  PIN q[89]
    DIRECTION OUTPUT ;
    USE SIGNAL ;
    PORT
      LAYER M5 ;
        RECT  17.472 11.688 17.496 11.88 ;
    END
  END q[89]
  PIN q[8]
    DIRECTION OUTPUT ;
    USE SIGNAL ;
    PORT
      LAYER M5 ;
        RECT  1.92 11.688 1.944 11.88 ;
    END
  END q[8]
  PIN q[90]
    DIRECTION OUTPUT ;
    USE SIGNAL ;
    PORT
      LAYER M5 ;
        RECT  17.664 11.688 17.688 11.88 ;
    END
  END q[90]
  PIN q[91]
    DIRECTION OUTPUT ;
    USE SIGNAL ;
    PORT
      LAYER M5 ;
        RECT  17.856 11.688 17.88 11.88 ;
    END
  END q[91]
  PIN q[92]
    DIRECTION OUTPUT ;
    USE SIGNAL ;
    PORT
      LAYER M5 ;
        RECT  18.048 11.688 18.072 11.88 ;
    END
  END q[92]
  PIN q[93]
    DIRECTION OUTPUT ;
    USE SIGNAL ;
    PORT
      LAYER M5 ;
        RECT  18.24 11.688 18.264 11.88 ;
    END
  END q[93]
  PIN q[94]
    DIRECTION OUTPUT ;
    USE SIGNAL ;
    PORT
      LAYER M5 ;
        RECT  18.432 11.688 18.456 11.88 ;
    END
  END q[94]
  PIN q[95]
    DIRECTION OUTPUT ;
    USE SIGNAL ;
    PORT
      LAYER M5 ;
        RECT  18.624 11.688 18.648 11.88 ;
    END
  END q[95]
  PIN q[96]
    DIRECTION OUTPUT ;
    USE SIGNAL ;
    PORT
      LAYER M5 ;
        RECT  18.816 11.688 18.84 11.88 ;
    END
  END q[96]
  PIN q[97]
    DIRECTION OUTPUT ;
    USE SIGNAL ;
    PORT
      LAYER M5 ;
        RECT  19.008 11.688 19.032 11.88 ;
    END
  END q[97]
  PIN q[98]
    DIRECTION OUTPUT ;
    USE SIGNAL ;
    PORT
      LAYER M5 ;
        RECT  19.2 11.688 19.224 11.88 ;
    END
  END q[98]
  PIN q[99]
    DIRECTION OUTPUT ;
    USE SIGNAL ;
    PORT
      LAYER M5 ;
        RECT  19.392 11.688 19.416 11.88 ;
    END
  END q[99]
  PIN q[9]
    DIRECTION OUTPUT ;
    USE SIGNAL ;
    PORT
      LAYER M5 ;
        RECT  2.112 11.688 2.136 11.88 ;
    END
  END q[9]
  PIN VDD
    DIRECTION INOUT ;
    USE POWER ;
    PORT
      LAYER M6 ;
        RECT  28.048 8.872 28.08 9.16 ;
        RECT  0 8.872 0.032 9.16 ;
        RECT  0 8.872 28.08 9.16 ;
        RECT  28.048 4.172 28.08 4.46 ;
        RECT  0 4.172 0.032 4.46 ;
        RECT  0 4.172 28.08 4.46 ;
      LAYER M2 ;
        RECT  28.062 11.061 28.08 11.079 ;
        RECT  0 11.061 0.018 11.079 ;
        RECT  28.062 10.521 28.08 10.539 ;
        RECT  0 10.521 0.018 10.539 ;
        RECT  28.062 9.981 28.08 9.999 ;
        RECT  0 9.981 0.018 9.999 ;
        RECT  28.062 9.441 28.08 9.459 ;
        RECT  0 9.441 0.018 9.459 ;
        RECT  28.062 8.901 28.08 8.919 ;
        RECT  0 8.901 0.018 8.919 ;
        RECT  28.062 8.361 28.08 8.379 ;
        RECT  0 8.361 0.018 8.379 ;
        RECT  28.062 7.821 28.08 7.839 ;
        RECT  0 7.821 0.018 7.839 ;
        RECT  28.062 7.281 28.08 7.299 ;
        RECT  0 7.281 0.018 7.299 ;
        RECT  28.062 6.741 28.08 6.759 ;
        RECT  0 6.741 0.018 6.759 ;
        RECT  28.062 6.201 28.08 6.219 ;
        RECT  0 6.201 0.018 6.219 ;
        RECT  28.062 5.661 28.08 5.679 ;
        RECT  0 5.661 0.018 5.679 ;
        RECT  28.062 5.121 28.08 5.139 ;
        RECT  0 5.121 0.018 5.139 ;
        RECT  28.062 4.581 28.08 4.599 ;
        RECT  0 4.581 0.018 4.599 ;
        RECT  28.062 4.041 28.08 4.059 ;
        RECT  0 4.041 0.018 4.059 ;
        RECT  28.062 3.501 28.08 3.519 ;
        RECT  0 3.501 0.018 3.519 ;
        RECT  28.062 2.961 28.08 2.979 ;
        RECT  0 2.961 0.018 2.979 ;
        RECT  28.062 2.421 28.08 2.439 ;
        RECT  0 2.421 0.018 2.439 ;
        RECT  28.062 1.881 28.08 1.899 ;
        RECT  0 1.881 0.018 1.899 ;
        RECT  28.062 1.341 28.08 1.359 ;
        RECT  0 1.341 0.018 1.359 ;
        RECT  28.062 0.801 28.08 0.819 ;
        RECT  0 0.801 0.018 0.819 ;
      LAYER M1 ;
        RECT  28.062 11.061 28.08 11.079 ;
        RECT  0 11.061 0.018 11.079 ;
        RECT  28.062 10.521 28.08 10.539 ;
        RECT  0 10.521 0.018 10.539 ;
        RECT  28.062 9.981 28.08 9.999 ;
        RECT  0 9.981 0.018 9.999 ;
        RECT  28.062 9.441 28.08 9.459 ;
        RECT  0 9.441 0.018 9.459 ;
        RECT  28.062 8.901 28.08 8.919 ;
        RECT  0 8.901 0.018 8.919 ;
        RECT  28.062 8.361 28.08 8.379 ;
        RECT  0 8.361 0.018 8.379 ;
        RECT  28.062 7.821 28.08 7.839 ;
        RECT  0 7.821 0.018 7.839 ;
        RECT  28.062 7.281 28.08 7.299 ;
        RECT  0 7.281 0.018 7.299 ;
        RECT  28.062 6.741 28.08 6.759 ;
        RECT  0 6.741 0.018 6.759 ;
        RECT  28.062 6.201 28.08 6.219 ;
        RECT  0 6.201 0.018 6.219 ;
        RECT  28.062 5.661 28.08 5.679 ;
        RECT  0 5.661 0.018 5.679 ;
        RECT  28.062 5.121 28.08 5.139 ;
        RECT  0 5.121 0.018 5.139 ;
        RECT  28.062 4.581 28.08 4.599 ;
        RECT  0 4.581 0.018 4.599 ;
        RECT  28.062 4.041 28.08 4.059 ;
        RECT  0 4.041 0.018 4.059 ;
        RECT  28.062 3.501 28.08 3.519 ;
        RECT  0 3.501 0.018 3.519 ;
        RECT  28.062 2.961 28.08 2.979 ;
        RECT  0 2.961 0.018 2.979 ;
        RECT  28.062 2.421 28.08 2.439 ;
        RECT  0 2.421 0.018 2.439 ;
        RECT  28.062 1.881 28.08 1.899 ;
        RECT  0 1.881 0.018 1.899 ;
        RECT  28.062 1.341 28.08 1.359 ;
        RECT  0 1.341 0.018 1.359 ;
        RECT  28.062 0.801 28.08 0.819 ;
        RECT  0 0.801 0.018 0.819 ;
    END
  END VDD
  PIN VSS
    DIRECTION INOUT ;
    USE GROUND ;
    PORT
      LAYER M6 ;
        RECT  28.048 8.296 28.08 8.584 ;
        RECT  0 8.296 0.032 8.584 ;
        RECT  0 8.296 28.08 8.584 ;
        RECT  28.048 3.596 28.08 3.884 ;
        RECT  0 3.596 0.032 3.884 ;
        RECT  0 3.596 28.08 3.884 ;
      LAYER M2 ;
        RECT  28.062 11.331 28.08 11.349 ;
        RECT  0 11.331 0.018 11.349 ;
        RECT  28.062 10.791 28.08 10.809 ;
        RECT  0 10.791 0.018 10.809 ;
        RECT  28.062 10.251 28.08 10.269 ;
        RECT  0 10.251 0.018 10.269 ;
        RECT  28.062 9.711 28.08 9.729 ;
        RECT  0 9.711 0.018 9.729 ;
        RECT  28.062 9.171 28.08 9.189 ;
        RECT  0 9.171 0.018 9.189 ;
        RECT  28.062 8.631 28.08 8.649 ;
        RECT  0 8.631 0.018 8.649 ;
        RECT  28.062 8.091 28.08 8.109 ;
        RECT  0 8.091 0.018 8.109 ;
        RECT  28.062 7.551 28.08 7.569 ;
        RECT  0 7.551 0.018 7.569 ;
        RECT  28.062 7.011 28.08 7.029 ;
        RECT  0 7.011 0.018 7.029 ;
        RECT  28.062 6.471 28.08 6.489 ;
        RECT  0 6.471 0.018 6.489 ;
        RECT  28.062 5.931 28.08 5.949 ;
        RECT  0 5.931 0.018 5.949 ;
        RECT  28.062 5.391 28.08 5.409 ;
        RECT  0 5.391 0.018 5.409 ;
        RECT  28.062 4.851 28.08 4.869 ;
        RECT  0 4.851 0.018 4.869 ;
        RECT  28.062 4.311 28.08 4.329 ;
        RECT  0 4.311 0.018 4.329 ;
        RECT  28.062 3.771 28.08 3.789 ;
        RECT  0 3.771 0.018 3.789 ;
        RECT  28.062 3.231 28.08 3.249 ;
        RECT  0 3.231 0.018 3.249 ;
        RECT  28.062 2.691 28.08 2.709 ;
        RECT  0 2.691 0.018 2.709 ;
        RECT  28.062 2.151 28.08 2.169 ;
        RECT  0 2.151 0.018 2.169 ;
        RECT  28.062 1.611 28.08 1.629 ;
        RECT  0 1.611 0.018 1.629 ;
        RECT  28.062 1.071 28.08 1.089 ;
        RECT  0 1.071 0.018 1.089 ;
        RECT  28.062 0.531 28.08 0.549 ;
        RECT  0 0.531 0.018 0.549 ;
      LAYER M1 ;
        RECT  28.062 11.331 28.08 11.349 ;
        RECT  0 11.331 0.018 11.349 ;
        RECT  28.062 10.791 28.08 10.809 ;
        RECT  0 10.791 0.018 10.809 ;
        RECT  28.062 10.251 28.08 10.269 ;
        RECT  0 10.251 0.018 10.269 ;
        RECT  28.062 9.711 28.08 9.729 ;
        RECT  0 9.711 0.018 9.729 ;
        RECT  28.062 9.171 28.08 9.189 ;
        RECT  0 9.171 0.018 9.189 ;
        RECT  28.062 8.631 28.08 8.649 ;
        RECT  0 8.631 0.018 8.649 ;
        RECT  28.062 8.091 28.08 8.109 ;
        RECT  0 8.091 0.018 8.109 ;
        RECT  28.062 7.551 28.08 7.569 ;
        RECT  0 7.551 0.018 7.569 ;
        RECT  28.062 7.011 28.08 7.029 ;
        RECT  0 7.011 0.018 7.029 ;
        RECT  28.062 6.471 28.08 6.489 ;
        RECT  0 6.471 0.018 6.489 ;
        RECT  28.062 5.931 28.08 5.949 ;
        RECT  0 5.931 0.018 5.949 ;
        RECT  28.062 5.391 28.08 5.409 ;
        RECT  0 5.391 0.018 5.409 ;
        RECT  28.062 4.851 28.08 4.869 ;
        RECT  0 4.851 0.018 4.869 ;
        RECT  28.062 4.311 28.08 4.329 ;
        RECT  0 4.311 0.018 4.329 ;
        RECT  28.062 3.771 28.08 3.789 ;
        RECT  0 3.771 0.018 3.789 ;
        RECT  28.062 3.231 28.08 3.249 ;
        RECT  0 3.231 0.018 3.249 ;
        RECT  28.062 2.691 28.08 2.709 ;
        RECT  0 2.691 0.018 2.709 ;
        RECT  28.062 2.151 28.08 2.169 ;
        RECT  0 2.151 0.018 2.169 ;
        RECT  28.062 1.611 28.08 1.629 ;
        RECT  0 1.611 0.018 1.629 ;
        RECT  28.062 1.071 28.08 1.089 ;
        RECT  0 1.071 0.018 1.089 ;
        RECT  28.062 0.531 28.08 0.549 ;
        RECT  0 0.531 0.018 0.549 ;
    END
  END VSS
  OBS
    LAYER RVTN ;
     RECT  0 0.54 28.08 0.675 ;
     RECT  0 0.945 28.08 1.215 ;
     RECT  0 1.485 28.08 1.755 ;
     RECT  0 2.025 28.08 2.295 ;
     RECT  0 2.565 28.08 2.835 ;
     RECT  0 3.105 28.08 3.375 ;
     RECT  0 3.645 28.08 3.915 ;
     RECT  0 4.185 28.08 4.455 ;
     RECT  0 4.725 28.08 4.995 ;
     RECT  0 5.265 28.08 5.535 ;
     RECT  0 5.805 28.08 6.075 ;
     RECT  0 6.345 28.08 6.615 ;
     RECT  0 6.885 28.08 7.155 ;
     RECT  0 7.425 28.08 7.695 ;
     RECT  0 7.965 28.08 8.235 ;
     RECT  0 8.505 28.08 8.775 ;
     RECT  0 9.045 28.08 9.315 ;
     RECT  0 9.585 28.08 9.855 ;
     RECT  0 10.125 28.08 10.395 ;
     RECT  0 10.665 28.08 10.935 ;
     RECT  0 11.205 28.08 11.34 ;
    LAYER RVTP ;
     RECT  0 0.675 28.08 0.945 ;
     RECT  0 1.215 28.08 1.485 ;
     RECT  0 1.755 28.08 2.025 ;
     RECT  0 2.295 28.08 2.565 ;
     RECT  0 2.835 28.08 3.105 ;
     RECT  0 3.375 28.08 3.645 ;
     RECT  0 3.915 28.08 4.185 ;
     RECT  0 4.455 28.08 4.725 ;
     RECT  0 4.995 28.08 5.265 ;
     RECT  0 5.535 28.08 5.805 ;
     RECT  0 6.075 28.08 6.345 ;
     RECT  0 6.615 28.08 6.885 ;
     RECT  0 7.155 28.08 7.425 ;
     RECT  0 7.695 28.08 7.965 ;
     RECT  0 8.235 28.08 8.505 ;
     RECT  0 8.775 28.08 9.045 ;
     RECT  0 9.315 28.08 9.585 ;
     RECT  0 9.855 28.08 10.125 ;
     RECT  0 10.395 28.08 10.665 ;
     RECT  0 10.935 28.08 11.205 ;
    LAYER M1 ;
     RECT  0 0.531 28.08 11.349 ;
    LAYER M2 ;
     RECT  0 0.531 28.08 11.349 ;
    LAYER M3 ;
     RECT  0.144 0.187 0.162 0.235 ;
     RECT  1.26 0.187 26.406 0.235 ;
     RECT  0.144 0.235 26.406 0.715 ;
     RECT  27.255 0.523 27.345 0.715 ;
     RECT  0.144 0.715 27.345 0.793 ;
     RECT  0.144 0.793 27.537 0.977 ;
     RECT  0.144 0.977 26.514 1.183 ;
     RECT  0.108 1.183 26.514 1.715 ;
     RECT  0.144 1.715 26.514 1.819 ;
     RECT  27.255 0.977 27.537 1.819 ;
     RECT  0.144 1.819 27.537 1.985 ;
     RECT  0.18 1.985 27.537 2.795 ;
     RECT  0.216 2.795 27.537 3.875 ;
     RECT  0.255 3.875 27.537 5.225 ;
     RECT  18.828 5.225 27.537 5.495 ;
     RECT  0.255 5.225 18.09 5.539 ;
     RECT  0.216 5.539 18.09 5.693 ;
     RECT  18.936 5.495 27.537 5.693 ;
     RECT  0.216 5.693 12.114 5.873 ;
     RECT  7.704 5.873 12.114 5.933 ;
     RECT  7.704 5.933 11.754 6.035 ;
     RECT  18.972 5.693 27.537 6.035 ;
     RECT  18.972 6.035 22.59 6.071 ;
     RECT  0.216 5.873 6.93 6.269 ;
     RECT  0.216 6.269 3.114 6.377 ;
     RECT  23.364 6.035 27.537 6.413 ;
     RECT  12.852 5.693 18.09 6.421 ;
     RECT  0.216 6.377 1.422 6.575 ;
     RECT  10.548 6.035 11.754 6.691 ;
     RECT  2.268 6.377 3.114 6.749 ;
     RECT  23.4 6.413 27.537 6.809 ;
     RECT  24.912 6.809 27.537 6.845 ;
     RECT  12.852 6.421 18.198 6.859 ;
     RECT  18.972 6.071 22.374 6.859 ;
     RECT  3.888 6.269 6.93 6.961 ;
     RECT  7.704 6.035 9.774 6.961 ;
     RECT  10.548 6.691 11.97 6.961 ;
     RECT  12.852 6.859 22.374 6.961 ;
     RECT  2.304 6.749 3.114 7.231 ;
     RECT  3.888 6.961 9.774 7.231 ;
     RECT  0.255 6.575 1.422 7.435 ;
     RECT  2.304 7.231 9.774 7.435 ;
     RECT  10.548 6.961 22.374 7.435 ;
     RECT  23.4 6.809 24.066 7.435 ;
     RECT  2.304 7.435 24.066 7.771 ;
     RECT  2.232 7.771 24.21 7.925 ;
     RECT  0.255 7.435 1.494 7.963 ;
     RECT  2.232 7.925 12.114 7.963 ;
     RECT  12.852 7.925 24.21 7.963 ;
     RECT  25.128 6.845 27.537 7.963 ;
     RECT  12.852 7.963 27.537 7.997 ;
     RECT  12.852 7.997 22.374 8.381 ;
     RECT  0.255 7.963 12.114 8.525 ;
     RECT  19.116 8.381 22.374 8.851 ;
     RECT  10.548 8.525 12.114 8.909 ;
     RECT  10.548 8.909 11.718 8.969 ;
     RECT  12.852 8.381 18.342 9.115 ;
     RECT  19.116 8.851 22.518 9.115 ;
     RECT  23.256 7.997 27.537 9.115 ;
     RECT  10.548 8.969 11.61 9.149 ;
     RECT  12.852 9.115 27.537 9.211 ;
     RECT  12.672 9.211 27.537 9.239 ;
     RECT  19.116 9.239 27.537 9.509 ;
     RECT  0.255 8.525 9.702 9.691 ;
     RECT  10.98 9.149 11.61 9.691 ;
     RECT  12.672 9.239 18.342 9.691 ;
     RECT  10.98 9.691 18.342 9.779 ;
     RECT  0.255 9.691 10.026 9.931 ;
     RECT  10.98 9.779 11.682 9.931 ;
     RECT  19.116 9.509 22.59 10.021 ;
     RECT  0.255 9.931 11.682 10.049 ;
     RECT  12.456 9.779 18.342 10.253 ;
     RECT  14.004 10.253 18.342 10.267 ;
     RECT  19.08 10.021 22.59 10.267 ;
     RECT  23.364 9.509 27.537 10.267 ;
     RECT  0.255 10.049 11.61 10.301 ;
     RECT  12.456 10.253 12.87 10.301 ;
     RECT  0.255 10.301 11.337 10.319 ;
     RECT  0.255 10.319 9.81 10.355 ;
     RECT  14.004 10.267 27.537 10.355 ;
     RECT  19.08 10.355 27.537 10.391 ;
     RECT  4.896 10.355 9.81 10.541 ;
     RECT  10.656 10.319 11.337 10.589 ;
     RECT  0.255 10.355 4.122 10.829 ;
     RECT  9.684 10.541 9.81 10.877 ;
     RECT  14.004 10.355 18.306 10.877 ;
     RECT  23.4 10.391 27.537 10.877 ;
     RECT  23.4 10.877 23.706 10.895 ;
     RECT  14.004 10.877 15.39 10.925 ;
     RECT  4.896 10.541 8.55 10.973 ;
     RECT  16.128 10.877 18.126 10.973 ;
     RECT  24.552 10.877 25.866 10.973 ;
     RECT  12.456 10.301 12.834 11.011 ;
     RECT  10.692 10.589 11.337 11.087 ;
     RECT  27.255 10.877 27.537 11.087 ;
     RECT  12.168 11.011 12.834 11.129 ;
     RECT  3.096 10.829 4.122 11.165 ;
     RECT  5.58 10.973 7.038 11.165 ;
     RECT  8.136 10.973 8.55 11.165 ;
     RECT  9.792 10.877 9.81 11.165 ;
     RECT  12.168 11.129 12.582 11.165 ;
     RECT  14.004 10.925 14.922 11.165 ;
     RECT  16.128 10.973 17.694 11.165 ;
     RECT  19.08 10.391 22.59 11.165 ;
     RECT  24.552 10.973 25.434 11.165 ;
     RECT  5.655 11.165 6.174 11.273 ;
     RECT  16.236 11.165 17.694 11.273 ;
     RECT  19.224 11.165 22.59 11.273 ;
     RECT  3.168 11.165 4.122 11.281 ;
     RECT  8.244 11.165 8.55 11.281 ;
     RECT  0.255 10.829 2.214 11.357 ;
     RECT  3.168 11.281 4.23 11.357 ;
     RECT  5.655 11.273 6.03 11.357 ;
     RECT  7.02 11.165 7.038 11.357 ;
     RECT  8.244 11.281 8.694 11.357 ;
     RECT  9.828 11.281 9.846 11.357 ;
     RECT  10.692 11.087 11.214 11.357 ;
     RECT  12.312 11.165 12.582 11.357 ;
     RECT  14.148 11.165 14.922 11.357 ;
     RECT  16.236 11.273 17.01 11.357 ;
     RECT  19.224 11.273 22.482 11.357 ;
     RECT  23.436 10.895 23.706 11.357 ;
     RECT  24.66 11.165 24.678 11.357 ;
     RECT  25.416 11.165 25.434 11.357 ;
     RECT  27.255 11.087 27.345 11.357 ;
     RECT  2.196 11.357 2.214 11.405 ;
     RECT  4.212 11.357 4.23 11.405 ;
     RECT  14.472 11.357 14.49 11.405 ;
     RECT  5.796 11.357 6.03 11.453 ;
     RECT  11.016 11.357 11.214 11.453 ;
     RECT  16.632 11.357 16.794 11.453 ;
     RECT  0.9 11.357 1.026 11.501 ;
     RECT  5.976 11.453 6.03 11.501 ;
     RECT  11.196 11.453 11.214 11.501 ;
     RECT  16.776 11.453 16.794 11.501 ;
     RECT  21.996 11.357 22.014 11.501 ;
     RECT  6.012 11.501 6.03 11.597 ;
     RECT  1.008 11.501 1.026 11.789 ;
    LAYER M4 ;
     RECT  0.133 0.192 0.248 0.216 ;
     RECT  0.133 1.824 0.248 1.848 ;
     RECT  0.133 2.88 0.248 2.904 ;
     RECT  0.133 3.936 0.248 3.96 ;
     RECT  0.133 5.184 0.248 5.208 ;
     RECT  0.248 0.192 0.373 11.352 ;
     RECT  0.373 0.192 0.544 11.496 ;
     RECT  0.544 0.192 0.641 5.112 ;
     RECT  0.544 8.784 0.659 11.496 ;
     RECT  0.659 9.696 0.949 11.496 ;
     RECT  0.641 4.56 0.973 5.112 ;
     RECT  0.544 6.864 0.973 7.464 ;
     RECT  0.949 9.696 0.997 11.688 ;
     RECT  0.997 9.696 1.081 11.784 ;
     RECT  0.973 4.56 1.145 4.584 ;
     RECT  1.081 9.696 1.433 11.4 ;
     RECT  1.525 6.192 1.537 6.36 ;
     RECT  0.973 7.44 1.571 7.464 ;
     RECT  0.641 0.192 1.621 3.432 ;
     RECT  1.621 0.192 1.645 3.576 ;
     RECT  1.433 9.696 1.657 9.768 ;
     RECT  1.573 7.968 1.667 8.376 ;
     RECT  1.667 8.352 1.669 8.376 ;
     RECT  1.657 9.696 1.715 9.72 ;
     RECT  1.537 5.616 1.721 6.36 ;
     RECT  1.669 8.352 1.793 8.472 ;
     RECT  1.721 5.712 1.865 6.36 ;
     RECT  1.645 0.192 2.185 4.536 ;
     RECT  1.433 10.8 2.225 11.4 ;
     RECT  2.204 8.496 2.291 8.52 ;
     RECT  2.185 0.192 2.293 4.584 ;
     RECT  2.101 6.72 2.297 6.744 ;
     RECT  2.225 10.8 2.485 11.352 ;
     RECT  2.293 0.192 2.833 4.68 ;
     RECT  1.865 5.712 2.833 5.736 ;
     RECT  2.725 8.544 2.869 8.568 ;
     RECT  2.485 10.704 3.049 11.352 ;
     RECT  2.869 8.544 3.089 9.144 ;
     RECT  3.049 10.32 3.193 11.352 ;
     RECT  3.089 8.544 3.301 9.096 ;
     RECT  2.833 0.192 3.329 5.736 ;
     RECT  3.301 8.352 3.329 9.096 ;
     RECT  3.329 7.968 3.509 9.096 ;
     RECT  3.193 10.272 3.637 11.352 ;
     RECT  3.329 0.192 3.737 6.264 ;
     RECT  3.737 0.192 3.989 4.968 ;
     RECT  3.509 7.44 4.097 9.096 ;
     RECT  3.637 10.272 4.213 11.4 ;
     RECT  3.737 6.192 4.237 6.264 ;
     RECT  4.213 10.224 4.241 11.4 ;
     RECT  4.097 7.44 4.309 8.904 ;
     RECT  4.241 10.224 4.385 10.968 ;
     RECT  4.237 6.192 4.405 6.312 ;
     RECT  4.309 7.392 4.405 8.904 ;
     RECT  4.405 6.192 4.601 8.904 ;
     RECT  4.601 7.44 5.173 8.904 ;
     RECT  4.601 6.192 5.269 6.264 ;
     RECT  3.989 0.192 5.309 4.68 ;
     RECT  5.269 5.712 5.309 6.264 ;
     RECT  4.385 10.272 5.365 10.968 ;
     RECT  5.365 10.272 5.557 11.448 ;
     RECT  5.309 0.192 5.648 6.264 ;
     RECT  5.173 7.44 5.648 9.192 ;
     RECT  5.557 10.272 5.648 11.496 ;
     RECT  5.648 0.192 5.749 11.496 ;
     RECT  5.749 0.192 5.944 11.592 ;
     RECT  5.944 10.848 6.041 11.592 ;
     RECT  5.944 0.192 6.545 7.368 ;
     RECT  5.944 8.544 6.545 9.096 ;
     RECT  6.545 8.544 6.581 9 ;
     RECT  6.581 8.544 6.851 8.568 ;
     RECT  6.545 6.864 6.985 7.368 ;
     RECT  6.985 7.248 7.049 7.368 ;
     RECT  6.041 10.848 7.049 11.352 ;
     RECT  6.545 0.192 7.085 5.448 ;
     RECT  7.049 10.848 7.801 10.968 ;
     RECT  7.669 7.392 7.861 7.416 ;
     RECT  7.801 10.272 7.957 10.968 ;
     RECT  7.957 9.648 8.053 10.968 ;
     RECT  7.085 0.192 8.161 5.064 ;
     RECT  8.161 0.192 8.245 6.312 ;
     RECT  7.861 7.392 8.449 8.376 ;
     RECT  8.053 9.648 8.449 11.352 ;
     RECT  8.245 0.192 8.597 5.832 ;
     RECT  8.449 7.392 8.716 11.352 ;
     RECT  8.716 7.392 8.773 10.872 ;
     RECT  8.773 6.864 8.867 10.872 ;
     RECT  8.597 0.192 9.565 5.736 ;
     RECT  9.565 0.192 9.649 6.312 ;
     RECT  8.867 7.344 9.713 10.872 ;
     RECT  9.649 0.192 9.749 5.928 ;
     RECT  9.713 7.344 9.785 10.296 ;
     RECT  9.781 11.328 10.741 11.352 ;
     RECT  9.749 2.88 10.885 5.928 ;
     RECT  9.785 7.44 10.885 10.296 ;
     RECT  10.741 11.328 10.885 11.448 ;
     RECT  9.749 0.192 10.933 1.704 ;
     RECT  10.933 0.192 11.048 1.8 ;
     RECT  10.885 2.88 11.048 11.448 ;
     RECT  11.048 0.192 11.125 11.448 ;
     RECT  11.125 0.192 11.225 11.496 ;
     RECT  11.225 0.192 11.344 11.208 ;
     RECT  11.344 8.88 11.363 11.208 ;
     RECT  11.363 8.88 11.621 10.296 ;
     RECT  11.621 8.88 11.693 9.768 ;
     RECT  11.344 0.192 11.809 7.896 ;
     RECT  11.809 0.192 11.891 5.976 ;
     RECT  11.809 7.2 11.945 7.896 ;
     RECT  11.693 8.88 12.125 9.72 ;
     RECT  11.891 0.192 12.565 4.008 ;
     RECT  12.277 11.328 12.593 11.352 ;
     RECT  12.565 0.192 12.737 3.96 ;
     RECT  11.891 5.136 12.803 5.976 ;
     RECT  12.661 10.848 12.809 10.872 ;
     RECT  12.125 9.696 12.812 9.72 ;
     RECT  12.812 9.696 12.899 10.296 ;
     RECT  11.945 7.44 13.045 7.896 ;
     RECT  12.737 2.832 13.105 3.96 ;
     RECT  12.803 5.184 13.141 5.976 ;
     RECT  12.899 9.696 13.196 10.248 ;
     RECT  13.045 7.392 13.237 7.896 ;
     RECT  13.196 9.36 13.237 10.248 ;
     RECT  13.141 5.184 13.381 6.264 ;
     RECT  13.237 7.392 13.381 10.248 ;
     RECT  13.381 5.184 13.385 10.248 ;
     RECT  12.737 0.192 13.429 1.704 ;
     RECT  13.385 9.12 13.493 10.248 ;
     RECT  13.493 9.12 13.565 10.2 ;
     RECT  13.105 2.832 13.673 3.432 ;
     RECT  13.385 5.184 13.673 8.088 ;
     RECT  13.673 5.184 13.885 7.896 ;
     RECT  14.005 11.328 14.176 11.352 ;
     RECT  13.565 9.12 14.243 10.056 ;
     RECT  13.885 4.704 14.428 7.896 ;
     RECT  14.176 11.328 14.501 11.4 ;
     RECT  14.492 9.072 14.579 9.096 ;
     RECT  13.673 2.832 14.605 3.336 ;
     RECT  13.429 0.192 14.629 1.128 ;
     RECT  14.561 10.224 14.645 10.248 ;
     RECT  14.428 6.864 14.713 7.896 ;
     RECT  14.629 0.192 14.725 1.272 ;
     RECT  14.605 2.304 14.725 3.336 ;
     RECT  14.428 4.704 14.732 5.16 ;
     RECT  14.725 0.192 14.773 3.336 ;
     RECT  14.732 4.56 14.773 5.16 ;
     RECT  14.501 11.328 14.773 11.352 ;
     RECT  14.773 0.192 14.819 5.16 ;
     RECT  14.713 6.864 14.819 8.568 ;
     RECT  14.819 5.088 14.867 5.16 ;
     RECT  14.773 10.848 14.933 11.352 ;
     RECT  14.867 5.088 14.969 5.112 ;
     RECT  14.819 0.192 15.113 1.704 ;
     RECT  14.819 2.688 15.148 3.96 ;
     RECT  14.819 6.864 15.685 7.992 ;
     RECT  15.685 9.552 15.733 9.576 ;
     RECT  15.733 8.976 15.893 9.576 ;
     RECT  15.148 2.688 15.925 3.768 ;
     RECT  15.893 5.136 15.973 5.16 ;
     RECT  15.973 5.136 16.069 5.64 ;
     RECT  15.685 6.768 16.069 7.992 ;
     RECT  15.925 2.304 16.117 3.768 ;
     RECT  16.069 4.8 16.117 7.992 ;
     RECT  15.893 8.976 16.117 9.672 ;
     RECT  14.933 10.848 16.117 10.92 ;
     RECT  16.117 2.256 16.165 7.992 ;
     RECT  16.117 8.976 16.165 9.72 ;
     RECT  15.113 0.192 16.261 1.128 ;
     RECT  16.165 2.256 16.261 9.72 ;
     RECT  16.117 10.848 16.309 11.352 ;
     RECT  16.261 0.192 16.448 9.72 ;
     RECT  16.309 10.848 16.448 11.448 ;
     RECT  16.448 0.192 16.501 11.448 ;
     RECT  16.501 0.192 16.744 11.496 ;
     RECT  16.744 10.272 16.805 11.496 ;
     RECT  16.744 0.192 16.979 9.144 ;
     RECT  16.805 10.272 17.021 11.352 ;
     RECT  16.979 1.584 17.123 7.416 ;
     RECT  17.123 6.816 17.129 7.416 ;
     RECT  17.129 7.344 17.237 7.416 ;
     RECT  17.123 1.584 17.363 5.736 ;
     RECT  17.363 1.68 17.417 5.736 ;
     RECT  17.417 2.88 17.507 5.736 ;
     RECT  17.021 10.272 17.548 10.92 ;
     RECT  17.417 1.68 17.641 1.704 ;
     RECT  17.507 5.664 17.669 5.736 ;
     RECT  17.548 10.848 18.037 10.92 ;
     RECT  16.979 8.544 18.229 9.144 ;
     RECT  18.037 10.848 18.317 10.968 ;
     RECT  17.507 2.88 18.353 4.584 ;
     RECT  17.237 7.344 18.601 7.368 ;
     RECT  18.229 8.352 18.601 9.144 ;
     RECT  18.353 2.88 18.613 3.912 ;
     RECT  17.669 5.664 18.637 5.688 ;
     RECT  16.979 0.192 18.709 0.216 ;
     RECT  18.601 7.344 18.716 9.144 ;
     RECT  18.613 2.832 18.737 3.912 ;
     RECT  18.637 5.136 18.755 5.688 ;
     RECT  18.716 6.864 18.803 9.144 ;
     RECT  18.737 2.688 18.821 3.912 ;
     RECT  18.755 5.328 18.893 5.688 ;
     RECT  18.716 10.32 18.925 10.344 ;
     RECT  18.893 5.664 18.961 5.688 ;
     RECT  18.709 0.192 19.333 1.128 ;
     RECT  18.925 10.272 19.379 10.344 ;
     RECT  18.821 2.784 19.765 3.912 ;
     RECT  18.961 5.664 19.813 6.312 ;
     RECT  18.803 7.344 19.813 8.52 ;
     RECT  19.333 0.192 19.825 1.704 ;
     RECT  19.765 2.784 19.825 4.584 ;
     RECT  19.825 0.192 19.909 4.584 ;
     RECT  19.813 5.664 19.909 8.52 ;
     RECT  18.805 11.328 19.957 11.352 ;
     RECT  19.909 0.192 20.009 8.52 ;
     RECT  20.009 1.68 20.051 8.52 ;
     RECT  20.051 7.872 20.101 8.52 ;
     RECT  20.101 7.872 20.188 9.384 ;
     RECT  20.051 1.68 20.189 6.84 ;
     RECT  20.189 2.208 20.693 6.84 ;
     RECT  20.188 7.872 21.013 9.096 ;
     RECT  20.009 0.192 21.02 0.312 ;
     RECT  19.957 10.848 21.061 11.352 ;
     RECT  21.02 0.192 21.589 1.128 ;
     RECT  20.693 2.208 21.589 6.264 ;
     RECT  21.589 0.192 21.725 6.264 ;
     RECT  21.013 7.44 21.725 9.096 ;
     RECT  21.061 10.224 21.725 11.352 ;
     RECT  21.725 0.192 21.848 6.312 ;
     RECT  21.725 7.44 21.848 11.352 ;
     RECT  21.848 0.192 21.877 11.352 ;
     RECT  21.877 0.192 22.025 11.496 ;
     RECT  22.025 0.192 22.144 11.352 ;
     RECT  22.144 0.192 22.259 6.12 ;
     RECT  22.144 7.44 22.277 9.144 ;
     RECT  22.259 2.112 22.313 6.12 ;
     RECT  22.313 2.112 22.444 5.832 ;
     RECT  22.277 7.44 23.125 7.992 ;
     RECT  22.277 9.12 23.125 9.144 ;
     RECT  23.125 6.864 23.267 7.992 ;
     RECT  23.125 9.12 23.267 9.24 ;
     RECT  22.444 2.304 23.317 5.832 ;
     RECT  23.267 7.584 23.317 7.992 ;
     RECT  22.144 10.272 23.389 11.352 ;
     RECT  23.317 7.584 23.404 8.472 ;
     RECT  23.404 7.584 23.411 8.376 ;
     RECT  23.411 7.92 23.429 8.376 ;
     RECT  23.317 2.304 23.653 6.552 ;
     RECT  22.259 0.192 23.845 1.128 ;
     RECT  23.653 2.304 23.845 6.456 ;
     RECT  23.389 9.696 24.365 11.352 ;
     RECT  23.429 7.968 24.685 8.376 ;
     RECT  24.365 9.696 24.685 10.056 ;
     RECT  24.685 7.968 24.797 10.056 ;
     RECT  24.797 7.968 25.043 9.72 ;
     RECT  23.845 0.192 25.045 6.456 ;
     RECT  25.043 7.968 25.045 9.144 ;
     RECT  25.045 0.192 25.139 9.144 ;
     RECT  25.139 1.68 25.228 9.144 ;
     RECT  25.228 6.864 25.229 9.144 ;
     RECT  25.229 6.864 25.283 7.992 ;
     RECT  25.283 7.344 25.301 7.992 ;
     RECT  25.228 1.68 25.324 5.4 ;
     RECT  25.324 1.68 25.331 5.208 ;
     RECT  24.365 11.328 25.333 11.352 ;
     RECT  25.229 9.12 25.373 9.144 ;
     RECT  25.333 10.848 25.445 11.352 ;
     RECT  25.331 1.68 25.468 5.16 ;
     RECT  25.468 1.68 25.481 3.432 ;
     RECT  25.301 7.44 25.667 7.992 ;
     RECT  25.468 4.512 25.733 5.16 ;
     RECT  25.667 7.968 25.805 7.992 ;
     RECT  25.445 10.848 25.955 10.968 ;
     RECT  25.481 1.68 26.057 2.904 ;
     RECT  26.057 1.68 26.099 2.472 ;
     RECT  25.139 0.192 26.417 0.216 ;
     RECT  26.099 1.68 26.773 1.848 ;
     RECT  26.773 0.528 27.248 1.848 ;
     RECT  25.733 5.136 27.248 5.16 ;
     RECT  25.955 10.848 27.248 10.872 ;
     RECT  27.248 0.528 27.352 11.352 ;
     RECT  27.352 0.798 27.544 11.082 ;
     RECT  27.544 1.68 27.683 1.704 ;
    LAYER M5 ;
     RECT  0.384 0.144 26.328 0.227 ;
     RECT  18.72 0.227 25.176 0.235 ;
     RECT  18.72 0.235 25.128 0.323 ;
     RECT  0.384 0.227 17.496 0.517 ;
     RECT  26.208 0.227 26.328 0.517 ;
     RECT  0.24 0.517 17.496 0.563 ;
     RECT  26.208 0.517 27.36 0.787 ;
     RECT  0.24 0.563 9.816 1.573 ;
     RECT  10.8 0.563 17.496 1.573 ;
     RECT  0.24 1.573 17.496 1.669 ;
     RECT  21.072 0.323 25.128 1.669 ;
     RECT  26.208 0.787 27.552 1.669 ;
     RECT  0.24 1.669 17.592 1.813 ;
     RECT  21.072 1.669 27.672 1.859 ;
     RECT  18.72 0.323 19.992 2.197 ;
     RECT  21.072 1.859 26.088 2.197 ;
     RECT  18.72 2.197 26.088 2.339 ;
     RECT  26.064 2.339 26.088 2.483 ;
     RECT  18.72 2.339 25.08 2.821 ;
     RECT  0.144 1.813 17.592 2.869 ;
     RECT  18.624 2.821 25.08 2.869 ;
     RECT  0.144 2.869 25.08 2.915 ;
     RECT  0.24 2.915 25.08 3.397 ;
     RECT  0.24 3.397 25.32 3.829 ;
     RECT  0.24 3.829 25.416 3.925 ;
     RECT  0.144 3.925 25.416 4.011 ;
     RECT  13.92 4.011 25.416 4.501 ;
     RECT  13.92 4.501 25.656 4.595 ;
     RECT  0.144 4.011 12.792 4.691 ;
     RECT  27.24 1.859 27.672 5.087 ;
     RECT  26.736 5.087 27.672 5.163 ;
     RECT  8.208 4.691 12.792 5.171 ;
     RECT  26.736 5.163 27.552 5.171 ;
     RECT  0.144 4.691 6.936 5.219 ;
     RECT  13.92 4.595 17.64 5.653 ;
     RECT  18.624 4.595 25.656 5.653 ;
     RECT  0.24 5.219 6.936 5.747 ;
     RECT  8.208 5.171 12.648 6.197 ;
     RECT  13.92 5.653 25.656 6.197 ;
     RECT  8.208 6.197 25.656 6.323 ;
     RECT  0.24 5.747 1.704 6.709 ;
     RECT  2.736 5.747 6.936 6.709 ;
     RECT  0.24 6.709 6.936 7.381 ;
     RECT  8.304 6.323 25.656 7.381 ;
     RECT  0.24 7.381 25.656 7.475 ;
     RECT  0.24 7.475 25.56 8.003 ;
     RECT  0.24 8.003 3.336 9.061 ;
     RECT  4.32 8.003 25.56 9.061 ;
     RECT  0.24 9.061 25.56 9.155 ;
     RECT  3.312 9.155 17.112 10.261 ;
     RECT  18.24 9.155 25.56 10.261 ;
     RECT  0.24 9.155 2.136 10.693 ;
     RECT  3.312 10.261 25.56 10.693 ;
     RECT  0.24 10.693 25.56 10.837 ;
     RECT  27.24 5.171 27.552 10.837 ;
     RECT  0.24 10.837 27.552 11.093 ;
     RECT  0.24 11.093 27.36 11.363 ;
     RECT  0.384 11.363 26.328 11.728 ;
     RECT  1.008 11.728 1.032 11.795 ;
    LAYER M6 ;
     RECT  0.613 1.664 2.197 1.696 ;
     RECT  0 3.596 2.197 4.46 ;
     RECT  2.197 1.664 2.915 4.46 ;
     RECT  2.915 1.664 3.011 1.696 ;
     RECT  2.915 3.456 3.397 4.46 ;
     RECT  0.144 5.952 3.397 5.984 ;
     RECT  0 8.296 3.397 9.16 ;
     RECT  3.397 3.456 3.589 5.984 ;
     RECT  3.397 8.296 4.501 10.336 ;
     RECT  4.501 8.128 4.595 10.336 ;
     RECT  3.589 3.456 4.739 6.24 ;
     RECT  4.739 3.456 6.229 4.576 ;
     RECT  4.739 5.952 6.323 6.24 ;
     RECT  6.229 2.752 6.805 4.576 ;
     RECT  6.805 1.536 7.475 4.576 ;
     RECT  7.475 1.728 8.099 4.46 ;
     RECT  8.099 1.728 8.579 1.76 ;
     RECT  4.595 8.128 9.061 9.16 ;
     RECT  9.061 8.128 9.203 9.76 ;
     RECT  6.323 5.952 9.253 5.984 ;
     RECT  8.099 3.328 9.923 4.46 ;
     RECT  9.203 8.296 11.459 9.76 ;
     RECT  9.253 5.952 12.563 6.24 ;
     RECT  11.459 8.296 13.237 9.16 ;
     RECT  12.563 6.208 13.429 6.24 ;
     RECT  9.923 3.596 14.773 4.46 ;
     RECT  14.773 2.752 14.821 4.46 ;
     RECT  13.429 6.208 15.731 6.816 ;
     RECT  13.237 8.296 15.731 9.568 ;
     RECT  15.731 8.296 16.261 9.16 ;
     RECT  15.731 6.208 16.307 6.24 ;
     RECT  14.821 2.752 17.219 4.832 ;
     RECT  16.261 8.128 18.757 9.16 ;
     RECT  17.219 3.596 19.237 4.46 ;
     RECT  19.141 1.024 20.003 1.056 ;
     RECT  18.757 8.128 20.005 10.336 ;
     RECT  19.237 3.456 20.437 4.46 ;
     RECT  20.437 2.88 21.061 4.46 ;
     RECT  20.005 7.552 21.107 10.336 ;
     RECT  21.061 2.88 21.299 4.576 ;
     RECT  21.107 7.552 21.683 10.208 ;
     RECT  21.683 8.296 22.883 10.208 ;
     RECT  21.299 3.596 22.931 4.576 ;
     RECT  22.931 3.596 23.893 4.46 ;
     RECT  23.893 3.456 24.851 4.46 ;
     RECT  25.093 1.024 25.141 1.056 ;
     RECT  25.141 0.192 25.573 1.056 ;
     RECT  25.573 0.192 26.243 1.76 ;
     RECT  26.243 1.024 26.291 1.76 ;
     RECT  24.851 3.596 26.725 4.46 ;
     RECT  26.291 1.728 26.819 1.76 ;
     RECT  26.725 3.596 27.683 5.152 ;
     RECT  27.683 3.596 28.08 4.46 ;
     RECT  22.883 8.296 28.08 9.16 ;
  END
END ot_attn_bank_sn136
END LIBRARY
